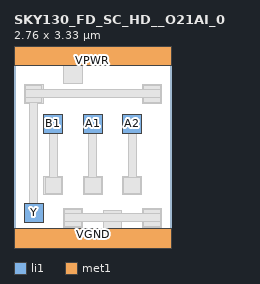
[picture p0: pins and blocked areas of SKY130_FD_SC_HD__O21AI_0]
MACRO SKY130_FD_SC_HD__O21AI_0
 CLASS CORE ;
 FOREIGN SKY130_FD_SC_HD__O21AI_0 0 0 ;
 SIZE 2.7600000000000002 BY 3.33 ;
 ORIGIN 0 0 ;
 SYMMETRY X Y R90 ;
 SITE unit ;
  PIN VPWR
   DIRECTION INOUT ;
   USE POWER ;
   SHAPE ABUTMENT ;
    PORT
     CLASS CORE ;
       LAYER li1 ;
        RECT 0.00000000 3.09000000 2.76000000 3.57000000 ;
       LAYER met1 ;
        RECT 0.00000000 3.09000000 2.76000000 3.57000000 ;
    END
  END VPWR

  PIN VGND
   DIRECTION INOUT ;
   USE POWER ;
   SHAPE ABUTMENT ;
    PORT
     CLASS CORE ;
       LAYER li1 ;
        RECT 0.00000000 -0.24000000 2.76000000 0.24000000 ;
       LAYER met1 ;
        RECT 0.00000000 -0.24000000 2.76000000 0.24000000 ;
    END
  END VGND

  PIN Y
   DIRECTION INOUT ;
   USE SIGNAL ;
   SHAPE ABUTMENT ;
    PORT
     CLASS CORE ;
       LAYER li1 ;
        RECT 0.18000000 0.35000000 0.51000000 0.68000000 ;
    END
  END Y

  PIN A1
   DIRECTION INOUT ;
   USE SIGNAL ;
   SHAPE ABUTMENT ;
    PORT
     CLASS CORE ;
       LAYER li1 ;
        RECT 1.21500000 1.90500000 1.54500000 2.23500000 ;
    END
  END A1

  PIN B1
   DIRECTION INOUT ;
   USE SIGNAL ;
   SHAPE ABUTMENT ;
    PORT
     CLASS CORE ;
       LAYER li1 ;
        RECT 0.52500000 1.90500000 0.85500000 2.23500000 ;
    END
  END B1

  PIN A2
   DIRECTION INOUT ;
   USE SIGNAL ;
   SHAPE ABUTMENT ;
    PORT
     CLASS CORE ;
       LAYER li1 ;
        RECT 1.90500000 1.90500000 2.23500000 2.23500000 ;
    END
  END A2

 OBS
    LAYER polycont ;
     RECT 0.60500000 0.90500000 0.77500000 1.07500000 ;
     RECT 1.29500000 0.90500000 1.46500000 1.07500000 ;
     RECT 1.98500000 0.90500000 2.15500000 1.07500000 ;
     RECT 0.60500000 1.98500000 0.77500000 2.15500000 ;
     RECT 1.29500000 1.98500000 1.46500000 2.15500000 ;
     RECT 1.98500000 1.98500000 2.15500000 2.15500000 ;

    LAYER pdiffc ;
     RECT 0.26000000 2.51000000 0.43000000 2.68000000 ;
     RECT 2.33000000 2.51000000 2.50000000 2.68000000 ;
     RECT 0.95000000 2.86000000 1.12000000 3.03000000 ;

    LAYER ndiffc ;
     RECT 1.64000000 0.30000000 1.81000000 0.47000000 ;
     RECT 0.95000000 0.34000000 1.12000000 0.51000000 ;
     RECT 2.33000000 0.34000000 2.50000000 0.51000000 ;
     RECT 0.26000000 0.43000000 0.43000000 0.60000000 ;

    LAYER li1 ;
     RECT 0.00000000 -0.24000000 2.76000000 0.24000000 ;
     RECT 1.56000000 0.24000000 1.89000000 0.55000000 ;
     RECT 0.87000000 0.26000000 1.20000000 0.59000000 ;
     RECT 2.25000000 0.26000000 2.58000000 0.59000000 ;
     RECT 0.18000000 0.35000000 0.51000000 0.68000000 ;
     RECT 0.52500000 0.82500000 0.85500000 1.15500000 ;
     RECT 1.21500000 0.82500000 1.54500000 1.15500000 ;
     RECT 1.90500000 0.82500000 2.23500000 1.15500000 ;
     RECT 0.52500000 1.90500000 0.85500000 2.23500000 ;
     RECT 1.21500000 1.90500000 1.54500000 2.23500000 ;
     RECT 1.90500000 1.90500000 2.23500000 2.23500000 ;
     RECT 0.18000000 2.43000000 0.51000000 2.76000000 ;
     RECT 2.25000000 2.43000000 2.58000000 2.76000000 ;
     RECT 0.87000000 2.78000000 1.20000000 3.09000000 ;
     RECT 0.00000000 3.09000000 2.76000000 3.57000000 ;

    LAYER viali ;
     RECT 1.64000000 -0.08500000 1.81000000 0.08500000 ;
     RECT 0.95000000 0.34000000 1.12000000 0.51000000 ;
     RECT 2.33000000 0.34000000 2.50000000 0.51000000 ;
     RECT 0.26000000 0.43000000 0.43000000 0.60000000 ;
     RECT 0.60500000 0.90500000 0.77500000 1.07500000 ;
     RECT 1.29500000 0.90500000 1.46500000 1.07500000 ;
     RECT 1.98500000 0.90500000 2.15500000 1.07500000 ;
     RECT 0.60500000 1.98500000 0.77500000 2.15500000 ;
     RECT 1.29500000 1.98500000 1.46500000 2.15500000 ;
     RECT 1.98500000 1.98500000 2.15500000 2.15500000 ;
     RECT 0.26000000 2.51000000 0.43000000 2.68000000 ;
     RECT 2.33000000 2.51000000 2.50000000 2.68000000 ;
     RECT 0.95000000 3.24500000 1.12000000 3.41500000 ;

    LAYER met1 ;
     RECT 0.00000000 -0.24000000 2.76000000 0.24000000 ;
     RECT 0.89000000 0.28000000 1.18000000 0.35500000 ;
     RECT 2.27000000 0.28000000 2.56000000 0.35500000 ;
     RECT 0.89000000 0.35500000 2.56000000 0.49500000 ;
     RECT 0.89000000 0.49500000 1.18000000 0.57000000 ;
     RECT 2.27000000 0.49500000 2.56000000 0.57000000 ;
     RECT 0.54500000 0.84500000 0.83500000 1.13500000 ;
     RECT 0.62000000 1.13500000 0.76000000 1.92500000 ;
     RECT 0.54500000 1.92500000 0.83500000 2.21500000 ;
     RECT 1.23500000 0.84500000 1.52500000 1.13500000 ;
     RECT 1.31000000 1.13500000 1.45000000 1.92500000 ;
     RECT 1.23500000 1.92500000 1.52500000 2.21500000 ;
     RECT 1.92500000 0.84500000 2.21500000 1.13500000 ;
     RECT 2.00000000 1.13500000 2.14000000 1.92500000 ;
     RECT 1.92500000 1.92500000 2.21500000 2.21500000 ;
     RECT 0.20000000 0.37000000 0.49000000 0.66000000 ;
     RECT 0.27500000 0.66000000 0.41500000 2.45000000 ;
     RECT 0.20000000 2.45000000 0.49000000 2.52500000 ;
     RECT 2.27000000 2.45000000 2.56000000 2.52500000 ;
     RECT 0.20000000 2.52500000 2.56000000 2.66500000 ;
     RECT 0.20000000 2.66500000 0.49000000 2.74000000 ;
     RECT 2.27000000 2.66500000 2.56000000 2.74000000 ;
     RECT 0.00000000 3.09000000 2.76000000 3.57000000 ;

    LAYER via ;


    LAYER met2 ;


    LAYER via2 ;


    LAYER met3 ;


 END
END SKY130_FD_SC_HD__O21AI_0
